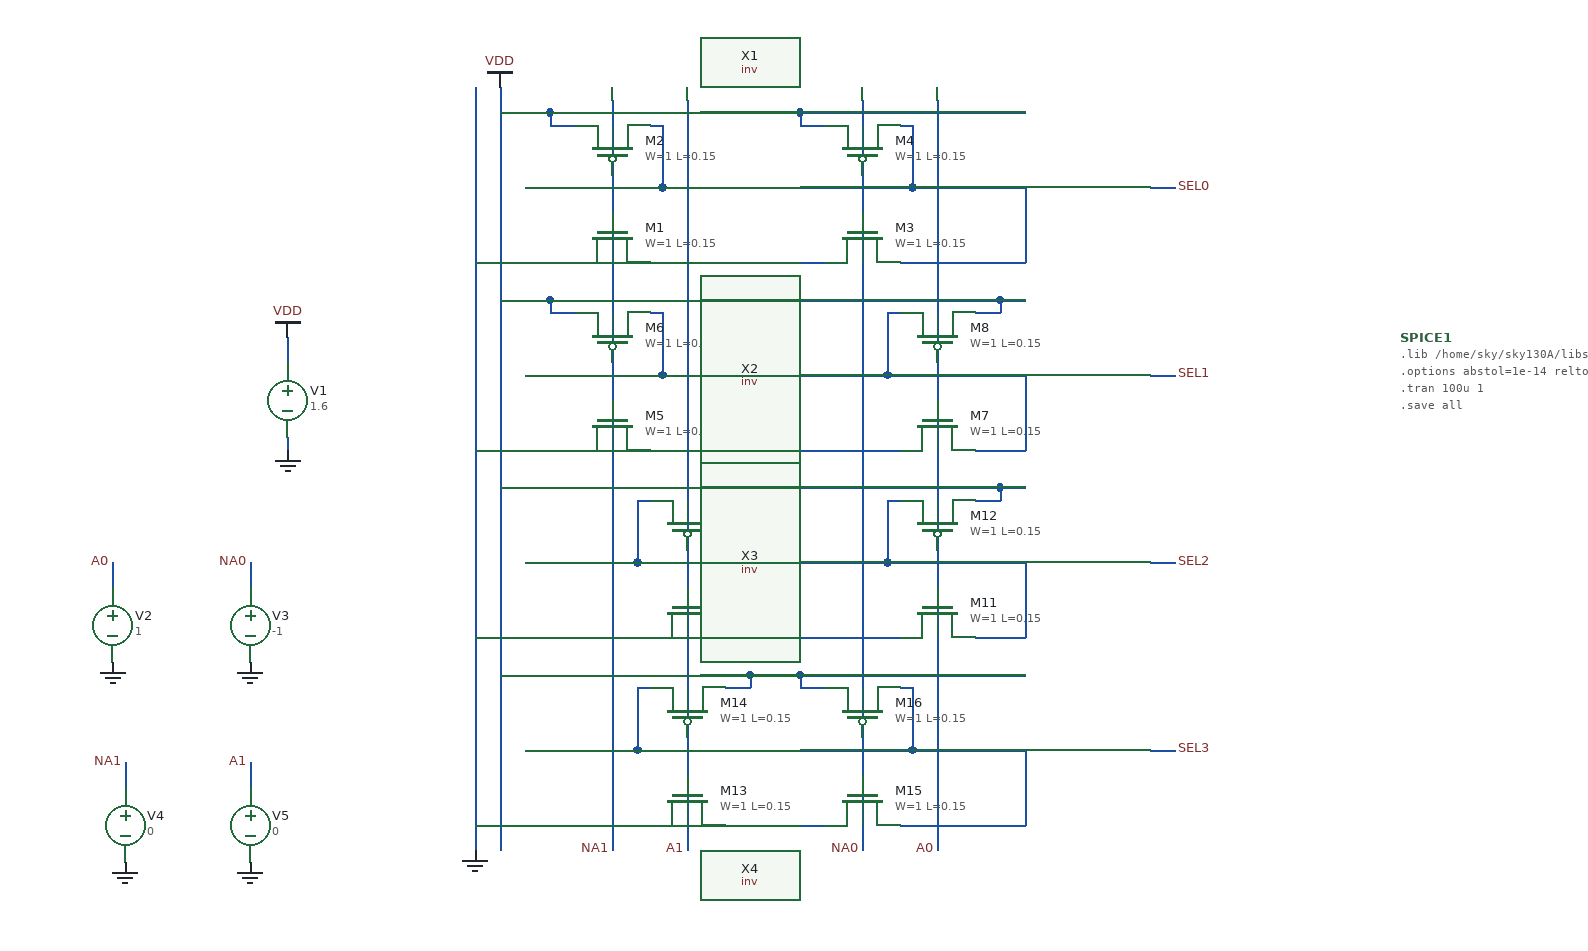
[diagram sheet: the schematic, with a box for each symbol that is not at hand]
v {xschem version=2.9.9 file_version=1.2 }
G {}
K {}
V {}
S {}
E {}
N 40 -110 60 -110 { lab=VDD}
N 40 -120 40 -110 { lab=VDD}
N 20 -120 40 -120 { lab=VDD}
N 90 -70 90 -40 { lab=NA1}
N 90 -40 90 20 { lab=NA1}
N 90 -130 90 -70 { lab=NA1}
N 120 -110 130 -110 { lab=#net1}
N 130 -110 130 -60 { lab=#net1}
N 20 -60 130 -60 { lab=#net1}
N 20 -0 60 0 { lab=GND}
N 150 -130 150 20 { lab=A1}
N 40 -120 220 -120 { lab=VDD}
N 130 -60 220 -60 { lab=#net1}
N 120 0 220 -0 { lab=#net2}
N 240 -110 260 -110 { lab=VDD}
N 240 -120 240 -110 { lab=VDD}
N 220 -120 240 -120 { lab=VDD}
N 290 -70 290 -40 { lab=NA0}
N 290 -40 290 20 { lab=NA0}
N 290 -130 290 -70 { lab=NA0}
N 320 -110 330 -110 { lab=#net1}
N 330 -110 330 -60 { lab=#net1}
N 220 -60 330 -60 { lab=#net1}
N 220 0 260 0 { lab=#net2}
N 350 -130 350 20 { lab=A0}
N 240 -120 420 -120 { lab=VDD}
N 330 -60 420 -60 { lab=#net1}
N 320 0 420 0 { lab=#net1}
N 40 40 60 40 { lab=VDD}
N 40 30 40 40 { lab=VDD}
N 20 30 40 30 { lab=VDD}
N 90 80 90 110 { lab=NA1}
N 90 110 90 170 { lab=NA1}
N 90 20 90 80 { lab=NA1}
N 120 40 130 40 { lab=#net3}
N 130 40 130 90 { lab=#net3}
N 20 90 130 90 { lab=#net3}
N 20 150 60 150 { lab=GND}
N 150 20 150 170 { lab=A1}
N 40 30 220 30 { lab=VDD}
N 130 90 220 90 { lab=#net3}
N 120 150 220 150 { lab=#net4}
N 380 40 400 40 { lab=VDD}
N 400 30 400 40 { lab=VDD}
N 400 30 420 30 { lab=VDD}
N 350 80 350 110 { lab=A0}
N 350 110 350 170 { lab=A0}
N 350 20 350 80 { lab=A0}
N 310 40 320 40 { lab=#net3}
N 310 40 310 90 { lab=#net3}
N 310 90 420 90 { lab=#net3}
N 380 150 420 150 { lab=#net3}
N 290 20 290 170 { lab=NA0}
N 220 30 400 30 { lab=VDD}
N 220 90 310 90 { lab=#net3}
N 220 150 320 150 { lab=#net4}
N 180 190 200 190 { lab=VDD}
N 200 180 200 190 { lab=VDD}
N 200 180 220 180 { lab=VDD}
N 150 230 150 260 { lab=A1}
N 150 260 150 320 { lab=A1}
N 150 170 150 230 { lab=A1}
N 110 190 120 190 { lab=#net5}
N 110 190 110 240 { lab=#net5}
N 110 240 220 240 { lab=#net5}
N 180 300 220 300 { lab=#net6}
N 90 170 90 320 { lab=NA1}
N 20 180 200 180 { lab=VDD}
N 20 240 110 240 { lab=#net5}
N 20 300 120 300 { lab=GND}
N 380 190 400 190 { lab=VDD}
N 400 180 400 190 { lab=VDD}
N 400 180 420 180 { lab=VDD}
N 350 230 350 260 { lab=A0}
N 350 260 350 320 { lab=A0}
N 350 170 350 230 { lab=A0}
N 310 190 320 190 { lab=#net5}
N 310 190 310 240 { lab=#net5}
N 310 240 420 240 { lab=#net5}
N 380 300 420 300 { lab=#net5}
N 290 170 290 320 { lab=NA0}
N 220 180 400 180 { lab=VDD}
N 220 240 310 240 { lab=#net5}
N 220 300 320 300 { lab=#net6}
N 180 340 200 340 { lab=VDD}
N 200 330 200 340 { lab=VDD}
N 200 330 220 330 { lab=VDD}
N 150 380 150 410 { lab=A1}
N 150 410 150 470 { lab=A1}
N 150 320 150 380 { lab=A1}
N 110 340 120 340 { lab=#net7}
N 110 340 110 390 { lab=#net7}
N 110 390 220 390 { lab=#net7}
N 180 450 220 450 { lab=#net8}
N 90 320 90 470 { lab=NA1}
N 20 330 200 330 { lab=VDD}
N 20 390 110 390 { lab=#net7}
N 20 450 120 450 { lab=GND}
N 240 340 260 340 { lab=VDD}
N 240 330 240 340 { lab=VDD}
N 220 330 240 330 { lab=VDD}
N 290 380 290 410 { lab=NA0}
N 290 410 290 470 { lab=NA0}
N 290 320 290 380 { lab=NA0}
N 320 340 330 340 { lab=#net7}
N 330 340 330 390 { lab=#net7}
N 220 390 330 390 { lab=#net7}
N 220 450 260 450 { lab=#net8}
N 350 320 350 470 { lab=A0}
N 240 330 420 330 { lab=VDD}
N 330 390 420 390 { lab=#net7}
N 320 450 420 450 { lab=#net7}
N -170 60 -170 80 { lab=VDD}
N -170 140 -170 150 { lab=GND}
N -0 -140 0 470 { lab=VDD}
N -20 -140 -20 470 { lab=GND}
N -0 -120 20 -120 { lab=VDD}
N -0 30 20 30 { lab=VDD}
N -0 180 20 180 { lab=VDD}
N -0 330 20 330 { lab=VDD}
N -20 450 20 450 { lab=GND}
N -20 300 20 300 { lab=GND}
N -20 150 20 150 { lab=GND}
N -20 -0 20 -0 { lab=GND}
N 420 240 420 300 { lab=#net5}
N 420 90 420 150 { lab=#net3}
N 420 -60 420 0 { lab=#net1}
N 420 390 420 450 { lab=#net7}
N 520 -60 540 -60 { lab=SEL0}
N 520 90 540 90 { lab=SEL1}
N 520 240 540 240 { lab=SEL2}
N 520 390 540 390 { lab=SEL3}
N -310 240 -310 260 { lab=A0}
N -200 240 -200 260 { lab=NA0}
N -300 400 -300 420 { lab=NA1}
N -200 400 -200 420 { lab=A1}
C {sky130_fd_pr/nfet_01v8.sym} 90 -20 1 0 {name=M1
L=0.15
W=1
nf=1 
mult=1
ad="'int((nf+1)/2) * W/nf * 0.29'" 
pd="'2*int((nf+1)/2) * (W/nf + 0.29)'"
as="'int((nf+2)/2) * W/nf * 0.29'" 
ps="'2*int((nf+2)/2) * (W/nf + 0.29)'"
nrd="'0.29 / W'" nrs="'0.29 / W'"
sa=0 sb=0 sd=0
model=nfet_01v8
spiceprefix=X
}
C {sky130_fd_pr/pfet_01v8.sym} 90 -90 3 0 {name=M2
L=0.15
W=1
nf=1
mult=1
ad="'int((nf+1)/2) * W/nf * 0.29'" 
pd="'2*int((nf+1)/2) * (W/nf + 0.29)'"
as="'int((nf+2)/2) * W/nf * 0.29'" 
ps="'2*int((nf+2)/2) * (W/nf + 0.29)'"
nrd="'0.29 / W'" nrs="'0.29 / W'"
sa=0 sb=0 sd=0
model=pfet_01v8
spiceprefix=X
}
C {sky130_fd_pr/nfet_01v8.sym} 290 -20 1 0 {name=M3
L=0.15
W=1
nf=1 
mult=1
ad="'int((nf+1)/2) * W/nf * 0.29'" 
pd="'2*int((nf+1)/2) * (W/nf + 0.29)'"
as="'int((nf+2)/2) * W/nf * 0.29'" 
ps="'2*int((nf+2)/2) * (W/nf + 0.29)'"
nrd="'0.29 / W'" nrs="'0.29 / W'"
sa=0 sb=0 sd=0
model=nfet_01v8
spiceprefix=X
}
C {sky130_fd_pr/pfet_01v8.sym} 290 -90 3 0 {name=M4
L=0.15
W=1
nf=1
mult=1
ad="'int((nf+1)/2) * W/nf * 0.29'" 
pd="'2*int((nf+1)/2) * (W/nf + 0.29)'"
as="'int((nf+2)/2) * W/nf * 0.29'" 
ps="'2*int((nf+2)/2) * (W/nf + 0.29)'"
nrd="'0.29 / W'" nrs="'0.29 / W'"
sa=0 sb=0 sd=0
model=pfet_01v8
spiceprefix=X
}
C {sky130_fd_pr/nfet_01v8.sym} 90 130 1 0 {name=M5
L=0.15
W=1
nf=1 
mult=1
ad="'int((nf+1)/2) * W/nf * 0.29'" 
pd="'2*int((nf+1)/2) * (W/nf + 0.29)'"
as="'int((nf+2)/2) * W/nf * 0.29'" 
ps="'2*int((nf+2)/2) * (W/nf + 0.29)'"
nrd="'0.29 / W'" nrs="'0.29 / W'"
sa=0 sb=0 sd=0
model=nfet_01v8
spiceprefix=X
}
C {sky130_fd_pr/pfet_01v8.sym} 90 60 3 0 {name=M6
L=0.15
W=1
nf=1
mult=1
ad="'int((nf+1)/2) * W/nf * 0.29'" 
pd="'2*int((nf+1)/2) * (W/nf + 0.29)'"
as="'int((nf+2)/2) * W/nf * 0.29'" 
ps="'2*int((nf+2)/2) * (W/nf + 0.29)'"
nrd="'0.29 / W'" nrs="'0.29 / W'"
sa=0 sb=0 sd=0
model=pfet_01v8
spiceprefix=X
}
C {sky130_fd_pr/nfet_01v8.sym} 350 130 3 1 {name=M7
L=0.15
W=1
nf=1 
mult=1
ad="'int((nf+1)/2) * W/nf * 0.29'" 
pd="'2*int((nf+1)/2) * (W/nf + 0.29)'"
as="'int((nf+2)/2) * W/nf * 0.29'" 
ps="'2*int((nf+2)/2) * (W/nf + 0.29)'"
nrd="'0.29 / W'" nrs="'0.29 / W'"
sa=0 sb=0 sd=0
model=nfet_01v8
spiceprefix=X
}
C {sky130_fd_pr/pfet_01v8.sym} 350 60 1 1 {name=M8
L=0.15
W=1
nf=1
mult=1
ad="'int((nf+1)/2) * W/nf * 0.29'" 
pd="'2*int((nf+1)/2) * (W/nf + 0.29)'"
as="'int((nf+2)/2) * W/nf * 0.29'" 
ps="'2*int((nf+2)/2) * (W/nf + 0.29)'"
nrd="'0.29 / W'" nrs="'0.29 / W'"
sa=0 sb=0 sd=0
model=pfet_01v8
spiceprefix=X
}
C {sky130_fd_pr/nfet_01v8.sym} 150 280 3 1 {name=M9
L=0.15
W=1
nf=1 
mult=1
ad="'int((nf+1)/2) * W/nf * 0.29'" 
pd="'2*int((nf+1)/2) * (W/nf + 0.29)'"
as="'int((nf+2)/2) * W/nf * 0.29'" 
ps="'2*int((nf+2)/2) * (W/nf + 0.29)'"
nrd="'0.29 / W'" nrs="'0.29 / W'"
sa=0 sb=0 sd=0
model=nfet_01v8
spiceprefix=X
}
C {sky130_fd_pr/pfet_01v8.sym} 150 210 1 1 {name=M10
L=0.15
W=1
nf=1
mult=1
ad="'int((nf+1)/2) * W/nf * 0.29'" 
pd="'2*int((nf+1)/2) * (W/nf + 0.29)'"
as="'int((nf+2)/2) * W/nf * 0.29'" 
ps="'2*int((nf+2)/2) * (W/nf + 0.29)'"
nrd="'0.29 / W'" nrs="'0.29 / W'"
sa=0 sb=0 sd=0
model=pfet_01v8
spiceprefix=X
}
C {sky130_fd_pr/nfet_01v8.sym} 350 280 3 1 {name=M11
L=0.15
W=1
nf=1 
mult=1
ad="'int((nf+1)/2) * W/nf * 0.29'" 
pd="'2*int((nf+1)/2) * (W/nf + 0.29)'"
as="'int((nf+2)/2) * W/nf * 0.29'" 
ps="'2*int((nf+2)/2) * (W/nf + 0.29)'"
nrd="'0.29 / W'" nrs="'0.29 / W'"
sa=0 sb=0 sd=0
model=nfet_01v8
spiceprefix=X
}
C {sky130_fd_pr/pfet_01v8.sym} 350 210 1 1 {name=M12
L=0.15
W=1
nf=1
mult=1
ad="'int((nf+1)/2) * W/nf * 0.29'" 
pd="'2*int((nf+1)/2) * (W/nf + 0.29)'"
as="'int((nf+2)/2) * W/nf * 0.29'" 
ps="'2*int((nf+2)/2) * (W/nf + 0.29)'"
nrd="'0.29 / W'" nrs="'0.29 / W'"
sa=0 sb=0 sd=0
model=pfet_01v8
spiceprefix=X
}
C {sky130_fd_pr/nfet_01v8.sym} 150 430 3 1 {name=M13
L=0.15
W=1
nf=1 
mult=1
ad="'int((nf+1)/2) * W/nf * 0.29'" 
pd="'2*int((nf+1)/2) * (W/nf + 0.29)'"
as="'int((nf+2)/2) * W/nf * 0.29'" 
ps="'2*int((nf+2)/2) * (W/nf + 0.29)'"
nrd="'0.29 / W'" nrs="'0.29 / W'"
sa=0 sb=0 sd=0
model=nfet_01v8
spiceprefix=X
}
C {sky130_fd_pr/pfet_01v8.sym} 150 360 1 1 {name=M14
L=0.15
W=1
nf=1
mult=1
ad="'int((nf+1)/2) * W/nf * 0.29'" 
pd="'2*int((nf+1)/2) * (W/nf + 0.29)'"
as="'int((nf+2)/2) * W/nf * 0.29'" 
ps="'2*int((nf+2)/2) * (W/nf + 0.29)'"
nrd="'0.29 / W'" nrs="'0.29 / W'"
sa=0 sb=0 sd=0
model=pfet_01v8
spiceprefix=X
}
C {sky130_fd_pr/nfet_01v8.sym} 290 430 1 0 {name=M15
L=0.15
W=1
nf=1 
mult=1
ad="'int((nf+1)/2) * W/nf * 0.29'" 
pd="'2*int((nf+1)/2) * (W/nf + 0.29)'"
as="'int((nf+2)/2) * W/nf * 0.29'" 
ps="'2*int((nf+2)/2) * (W/nf + 0.29)'"
nrd="'0.29 / W'" nrs="'0.29 / W'"
sa=0 sb=0 sd=0
model=nfet_01v8
spiceprefix=X
}
C {sky130_fd_pr/pfet_01v8.sym} 290 360 3 0 {name=M16
L=0.15
W=1
nf=1
mult=1
ad="'int((nf+1)/2) * W/nf * 0.29'" 
pd="'2*int((nf+1)/2) * (W/nf + 0.29)'"
as="'int((nf+2)/2) * W/nf * 0.29'" 
ps="'2*int((nf+2)/2) * (W/nf + 0.29)'"
nrd="'0.29 / W'" nrs="'0.29 / W'"
sa=0 sb=0 sd=0
model=pfet_01v8
spiceprefix=X
}
C {devices/vsource.sym} -170 110 0 0 {name=V1 value=1.6}
C {devices/vdd.sym} -170 60 0 0 {name=l1 lab=VDD}
C {devices/gnd.sym} -170 150 0 0 {name=l2 lab=GND}
C {devices/vdd.sym} 0 -140 0 0 {name=l3 lab=VDD}
C {devices/gnd.sym} -20 470 0 0 {name=l4 lab=GND}
C {/home/sky/Desktop/cochlea_sky130/xschem/HW4_RAM_readout/inv/inv.sym} 470 -60 0 0 {name=X1}
C {/home/sky/Desktop/cochlea_sky130/xschem/HW4_RAM_readout/inv/inv.sym} 470 90 0 0 {name=X2}
C {/home/sky/Desktop/cochlea_sky130/xschem/HW4_RAM_readout/inv/inv.sym} 470 240 0 0 {name=X3}
C {/home/sky/Desktop/cochlea_sky130/xschem/HW4_RAM_readout/inv/inv.sym} 470 390 0 0 {name=X4}
C {devices/lab_pin.sym} 540 -60 0 1 {name=l5 sig_type=std_logic lab=SEL0}
C {devices/lab_pin.sym} 540 90 0 1 {name=l6 sig_type=std_logic lab=SEL1}
C {devices/lab_pin.sym} 540 240 0 1 {name=l7 sig_type=std_logic lab=SEL2}
C {devices/lab_pin.sym} 540 390 0 1 {name=l8 sig_type=std_logic lab=SEL3}
C {devices/lab_pin.sym} 90 470 1 1 {name=l9 sig_type=std_logic lab=NA1}
C {devices/lab_pin.sym} 150 470 1 1 {name=l10 sig_type=std_logic lab=A1}
C {devices/lab_pin.sym} 350 470 1 1 {name=l11 sig_type=std_logic lab=A0}
C {devices/lab_pin.sym} 290 470 1 1 {name=l12 sig_type=std_logic lab=NA0}
C {devices/vsource.sym} -310 290 0 0 {name=V2 value=1}
C {devices/lab_pin.sym} -310 240 2 1 {name=l13 sig_type=std_logic lab=A0}
C {devices/gnd.sym} -310 320 0 0 {name=l14 lab=GND}
C {devices/lab_pin.sym} -200 240 2 1 {name=l15 sig_type=std_logic lab=NA0}
C {devices/vsource.sym} -200 290 0 0 {name=V3 value=-1}
C {devices/gnd.sym} -200 320 0 0 {name=l16 lab=GND}
C {devices/lab_pin.sym} -300 400 2 1 {name=l17 sig_type=std_logic lab=NA1}
C {devices/lab_pin.sym} -200 400 2 1 {name=l18 sig_type=std_logic lab=A1}
C {devices/vsource.sym} -300 450 0 0 {name=V4 value=0}
C {devices/gnd.sym} -300 480 0 0 {name=l19 lab=GND}
C {devices/vsource.sym} -200 450 0 0 {name=V5 value=0}
C {devices/gnd.sym} -200 480 0 0 {name=l20 lab=GND}
C {devices/code_shown.sym} 720 60 0 0 {name=SPICE1 only_toplevel=false value="
.lib /home/sky/sky130A/libs.tech/ngspice/sky130.lib.spice tt
.options abstol=1e-14 reltol=1e-4

.tran 100u 1
.save all
"}
